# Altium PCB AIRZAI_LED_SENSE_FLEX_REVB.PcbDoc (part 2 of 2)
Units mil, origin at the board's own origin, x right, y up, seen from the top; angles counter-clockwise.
Board outline 2713.44 x 4393.69 mil, 2 copper layers (Top Layer, Bottom Layer); 53 components, 36 nets, 162 pads, 79 vias.
Unrouted connection lines stored in the file: 83.

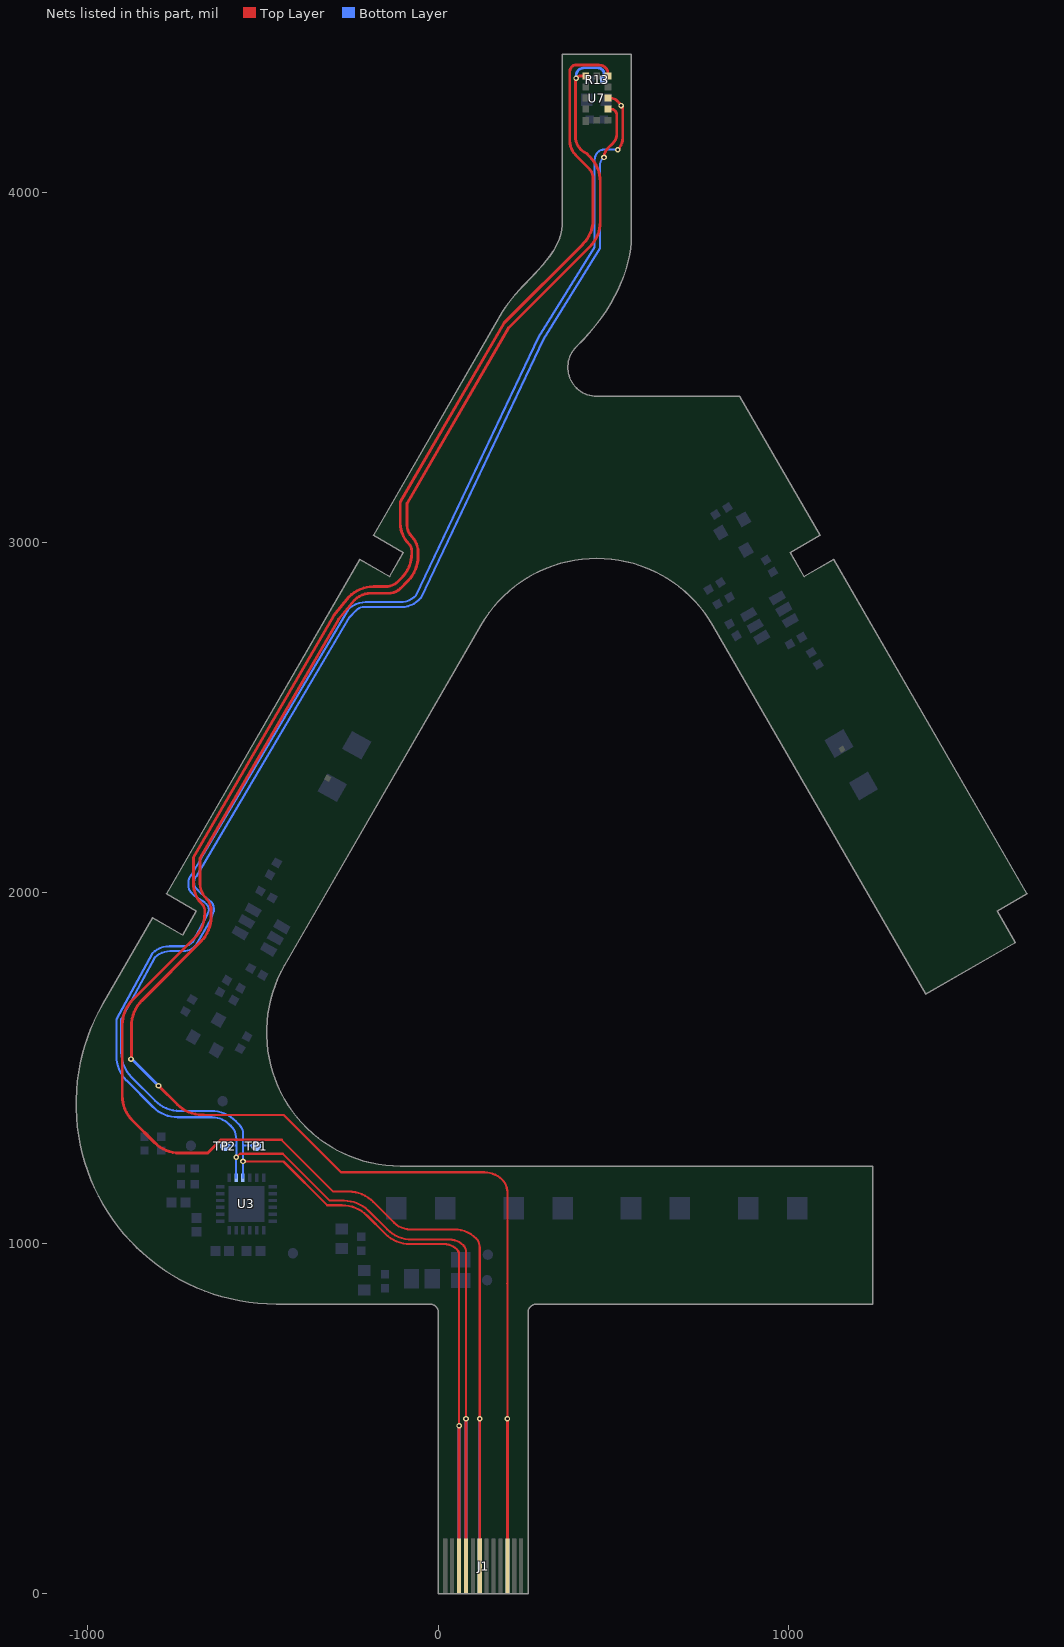
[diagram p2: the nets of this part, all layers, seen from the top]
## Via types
v1: diameter 16, hole 8, Top Layer to Bottom Layer, tented both sides, 49 vias
v2: diameter 20, hole 10, Top Layer to Bottom Layer, tented both sides, 25 vias
v3: diameter 20, hole 8, Top Layer to Bottom Layer, 5 vias

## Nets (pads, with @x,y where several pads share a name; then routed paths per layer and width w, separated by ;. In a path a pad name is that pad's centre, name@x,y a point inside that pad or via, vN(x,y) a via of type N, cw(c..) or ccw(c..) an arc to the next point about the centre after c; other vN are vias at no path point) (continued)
SCL: J1.10 TP1.1 U3.9 U7.10 | length 5932.2
  Top Layer w6: v1(-557.58,1234) -442,1234 -317,1109 -274.42,1109 cw(c-274.42,1009) -203.71,1079.71 -151.29,1027.29 ccw(c-80.58,1098) -80.58,998 16.79,998 cw(c16.79,946.79) 53,983 cw(c38.38,968.38) 59.06,968.38 v1(59.06,480)
  Top Layer w8: J1.10@59.06,78.74 v1(59.06,480) ; v1(472.68,4099) cw(c508.14,4099) 483.07,4124.07 498.39,4139.39 ccw(c472.79,4165) 509,4165 509,4218.51 ccw(c488.51,4218.51) 503,4233 ccw(c494.54,4224.54) 494.54,4236.5 U7.10@483.5,4236.5
  Bottom Layer w6: U3.9@-557.58,1187.42 v1(-557.58,1234) -557.58,1279 ; TP1.1@-520.09,1278 ccw(c-522.51,1275.59) -522.51,1279 -557.58,1279 ; v1(472.68,4099) 472.68,4101.68 ccw(c500.9,4073.47) 461,4073.47 461,3839.84 299.86,3580.26 -50,2842 -56,2836 cw(c-104.28,2884.28) -104.28,2816 -212,2816 ccw(c-212,2784.72) -234.11,2806.84 -253.65,2787.31 -690.55,2048 ccw(c-674.98,2032.43) -697,2032.43 -697,2029 ccw(c-672.08,2029) -689.7,2011.38 -676.16,1997.84 -648.57,1975 cw(c-666.86,1956.71) -641,1956.71 -641,1946.92 -649.15,1925.26 -693.49,1848.49 cw(c-728.48,1883.48) -728.48,1834 -766.1,1834 ccw(c-766.1,1773.8) -808.67,1816.37 -905,1640 -905,1545.42 ccw(c-805,1545.42) -875.71,1474.71 -808.29,1407.29 ccw(c-737.58,1478) -737.58,1378 -648.42,1378 cw(c-648.42,1278) -577.71,1348.71 -568,1339 cw(c-593.15,1313.85) -557.58,1313.85 -557.58,1279
  Bottom Layer w8: J1.10@59.06,78.74 v1(59.06,480)
SDA: J1.9 TP2.1 U3.8 U7.9 | length 6081.4
  Top Layer w6: v1(-576.57,1245.99) -566.56,1256 -444,1256 -310,1122 -269.42,1122 cw(c-269.42,1022) -198.71,1092.71 -146.29,1040.29 ccw(c-75.58,1111) -75.58,1011 32,1011 cw(c32,955.47) 71.26,994.74 72,994 cw(c55.73,977.73) 78.74,977.73 v1(78.74,499.74)
  Top Layer w8: J1.9@78.74,78.74 v1(78.74,499.74) ; U7.9@483.5,4268 490.97,4268 cw(c490.97,4238.97) 511.5,4259.5 cw(c465.63,4213.63) v1(521.48,4246.62) cw(c510.56,4235.7) 526,4235.7 526,4154.8 cw(c478.2,4154.8) v1(512,4121)
  Bottom Layer w6: TP2.1@-613.6,1278 cw(c-611.18,1275.59) -611.18,1279 -576.57,1279 ; U3.8@-577.27,1187.42 -577.27,1241.3 v1@-576.57,1241.99 ; v1(-576.57,1245.99) -576.57,1279 ; v1(512,4121) 471.9,4121 ccw(c471.9,4097.1) 455,4114 ccw(c476.73,4092.27) 446,4092.27 446,3843 286,3586 -64,2848.49 cw(c-108.63,2893.12) -108.63,2830 -207.74,2830 ccw(c-207.74,2760.9) -256.6,2809.76 -705,2051 ccw(c-685.69,2031.69) -713,2031.69 -713,2022 ccw(c-681.37,2022) -703.73,1999.63 -696.17,1992.07 -668,1974 -661.36,1967.36 cw(c-676.73,1952) -655,1952 -658.4,1940.2 -663,1931 -702,1859.59 cw(c-729.97,1887.56) -729.97,1848 -767.72,1848 ccw(c-767.72,1779.72) -816,1828 -919,1639.42 -919,1535.48 ccw(c-819,1535.48) -889.71,1464.77 -814.23,1389.29 ccw(c-743.52,1460) -743.52,1360 -646,1360 cw(c-646,1289.6) -596.22,1339.38 -591.84,1335 cw(c-628.69,1298.15) -576.57,1298.15 -576.57,1279
  Bottom Layer w8: J1.9@78.74,78.74 v1(78.74,499.74) v1@79,500
TOFINT: J1.7 U7.7 | length 6190.3
  Top Layer w6: -448,1296 -300,1148 -256.42,1148 cw(c-256.42,1048) -185.71,1118.71 -126,1059 ccw(c-80.13,1104.87) -80.13,1040 45.23,1040 cw(c45.23,951.23) 108,1014 cw(c83.59,989.59) 118.11,989.59 118.11,933.89 ; 118,934 118.11,933.89 ; v1(118.11,499.74) 118.11,933.89
  Top Layer w8: -448,1296 -620,1296 -658,1258 -738.58,1258 cw(c-738.58,1358) -809.29,1287.29 -872.71,1350.71 cw(c-802,1421.42) -902,1421.42 -902,1623.54 cw(c-802,1623.54) -872.71,1694.25 -695.73,1871.23 ccw(c-766.44,1941.94) -666.44,1941.94 -666.44,1949.2 ccw(c-693.76,1949.2) -674.44,1968.52 cw(c-615.2,2027.76) -698.98,2027.76 -698.98,2101 -298.8,2791.31 -255.63,2844.88 cw(c-184.92,2774.17) -184.92,2874.17 -150.8,2874.17 ccw(c-150.8,2924.8) -115,2889 -105.29,2898.71 ccw(c-176,2969.42) -76,2969.42 -76,2976.69 ccw(c-103.31,2976.69) -84,2996 cw(c-24.75,3055.25) -108.54,3055.25 -108.54,3115.47 188,3627 412.21,3851.21 ccw(c341.5,3921.92) 441.5,3921.92 441.5,4038 ccw(c397.86,4038) 428.72,4068.86 403.11,4094.46 391.79,4105.79 cw(c432.31,4146.31) 375,4146.31 375,4343.51 cw(c395.49,4343.51) 381,4358 cw(c391.85,4347.15) 391.85,4362.5 458.47,4362.5 cw(c458.47,4335.59) 477.5,4354.61 cw(c463.01,4340.13) 483.5,4340.13 U7.7@483.5,4330.99 ; J1.7@118.11,78.74 v1(118.11,499.74)
  Bottom Layer w8: J1.7@118.11,78.74 v1(118.11,499.74)
XSHUNT: J1.3 R13.2 U7.5 | length 6231.7
  Top Layer w6: -670.55,1367 -442,1367 -278,1203 131.3,1203 cw(c131.3,1131.3) 182,1182 cw(c146.15,1146.15) 196.85,1146.15 196.85,885.15 ; 196,886 196.85,885.15 ; v1(196.85,499.74) 196.85,885.15
  Top Layer w8: v1@-875.71,1526 -875.71,1621.87 cw(c-775.71,1621.87) -846.42,1692.58 -677.86,1861.14 ccw(c-748.57,1931.85) -648.57,1931.85 -648.57,1951.59 ccw(c-694.41,1951.59) -662,1984 cw(c-618.9,2027.1) -679.85,2027.1 -679.85,2099.9 -284.96,2781.09 -239,2836 cw(c-193.13,2790.13) -193.13,2855 -142.34,2855 ccw(c-142.34,2902.8) -108.54,2869 -87.29,2890.25 ccw(c-158,2960.96) -58,2960.96 -58,2973.54 ccw(c-119.46,2973.54) -76,3017 cw(c-44.2,3048.8) -89.17,3048.8 -89.17,3112.1 201.5,3613.5 432.4,3844.4 ccw(c361.69,3915.11) 461.69,3915.11 461.69,4029.89 ccw(c361.69,4029.89) 432.4,4100.6 422.23,4110.77 ; v1(-798.55,1450) -744.84,1396.29 ccw(c-674.13,1467) -674.13,1367 -670.55,1367 ; J1.3@196.85,78.74 v1(196.85,499.74) ; U7.5@420.5,4330.99 404.18,4330.99 ccw(c404.18,4320.88) 397.03,4328.03 393,4324 ccw(c397.83,4319.17) 391,4319.17 391,4158.91 ccw(c443.91,4158.91) 406.5,4121.5 ccw(c442.71,4157.71) 422.23,4110.77 ; 422,4111 422.23,4110.77
  Bottom Layer w8: v1(-877,1526) cw(c-877,1520.08) v1@-872.82,1524.27 ; v1@-872.81,1524.27 v1(-798.55,1450) ; J1.3@196.85,78.74 v1(196.85,499.74) ; v1(393,4325) 393,4331.1 cw(c416.9,4331.1) 400,4348 cw(c415.97,4332.03) 415.97,4354.61 454.45,4354.61 cw(c454.45,4335.45) 468,4349 cw(c456.69,4337.69) 472.69,4337.69 R13.2@472.69,4321
pads on no net: U3.11 U3.12 U3.13 U3.14 U3.15 U7.8

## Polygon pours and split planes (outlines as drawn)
GND on Bottom Layer "gnd bot" (hatched 45Degree grid 30 track 9.5, remove dead copper, pour order 8): -463,826.78 -23.39,826.77 cw(c-23.88,802.89) 0,802.41 0,0 255.91,0 255.91,802.77 cw(c279.78,802.89) 279.66,826.77 1239.37,826.77 1239.37,1220.44 -108.39,1220.47 cw(c-108.38,1602.36) -439.1,1793.32 121.28,2763.87 cw(c452,2572.92) 782.73,2763.85 1390.38,1711.31 1646.29,1858.61 1594.5,1948.32 1679.74,1997.53 1128.6,2952.19 1043.36,2902.98 1003.99,2971.17 1089.23,3020.38 860.08,3417.3 452.02,3417.31 cw(c452.02,3499.99) 394.16,3559.04 ccw(c-49.74,4012.89) 464.84,3641.1 ccw(c24.31,3959.43) 503.7,3703.33 ccw(c91.77,3922.61) 519.55,3736.13 ccw(c138.88,3902.12) 532.52,3769.79 ccw(c183.5,3887.15) 542.24,3804.11 ccw(c239.31,3875.17) 550.46,3874 550.46,3952.74 550.46,4393.69 353.61,4393.69 353.61,3952.75 353.61,3913.38 cw(c222.06,3913.41) 350.2,3883.68 cw(c204.05,3917.92) 340.75,3855.9 cw(c158.18,3938.86) 326.37,3829.65 cw(c73.79,3993.55) 308.19,3804.57 cw(c-93.59,4128.16) 287.35,3780.27 cw(c-627.68,4615.35) 264.96,3756.39 242.17,3732.54 ccw(c839.65,3165.01) 220.1,3708.36 ccw(c465.09,3488.64) 182.62,3657.47 -185.21,3020.41 -99.97,2971.2 -139.35,2903.01 -224.58,2952.23 -775.77,1997.6 -690.53,1948.38 -729.91,1880.19 -815.14,1929.41 -957.36,1683.09 ccw(c-462.98,1397.65)
3V3 on Bottom Layer "3.3V_1" (solid, remove dead copper, pour order 2): -299.03,953 ccw(c-299.08,916.43) -325,942.24 -407.37,859.87 cw(c-464.97,917.41) -465,836 -488,836.87 -531.37,840.54 -586.19,849 -625.1,859 -710,892 -772.94,928 -817,962.74 -852,993 -879,1019.83 -920,1068 -953,1122.18 -984,1183.85 -1001.44,1232.83 -1019,1301.68 -1025,1349 -1027,1414 -1023,1467 -1015,1514 -1005,1557 -992,1598 -971,1645 -945,1691 -884,1796 -829.8,1889.64 -826.08,1893.36 cw(c-803.06,1870.34) -803,1902.92 -794.09,1901.67 -781,1899 -770,1894 -734,1875 ccw(c-730.86,1879.5) -729.91,1874.09 -727.7,1874.7 ccw(c-728.35,1877.36) -726,1875.94 -722.61,1880.19 -684.76,1944 ccw(c-691.51,1947.87) -684,1950 -685,1952 ccw(c-688.28,1950.69) -687,1954 -728,1978 -740,1989 cw(c-713.9,2018.2) -753,2016 -752.07,2023.09 -751,2027 -740,2046.09 -726,2069.97 -256.34,2876 -243,2868 -727.7,2031 -732,2021 -732,2016 -729.91,2010 -727.7,2006.13 -720.59,1999.01 -709.31,1989 -698.79,1981.21 -691,1974 -685,1971 -677.3,1965.3 -669.76,1957 -666.74,1951 -666.74,1944 -673.08,1930.92 -698,1884 -707,1871 -712.2,1863.49 -722.61,1858 -742.74,1857 -785.05,1855.95 -803.8,1853.97 -815.14,1850.61 -821,1847 -829.8,1835.06 -886.05,1724.05 -922,1664 -950.5,1611.5 -974,1555 -984,1504 -992,1430 -992,1359 -982,1281 -960.43,1207.43 -929.11,1137.89 -901.5,1083.5 -869,1041.25 -829.8,1005 -764.28,950 -704,912.78 -623,884 -576.26,872.48 -524,865 -475,866 -444.15,876 -422,892.73 -406,913 -389,935 -370,958 -354,975 -336,993 -325,997.62 -285,998 -284,998 -284,953
3V3 on Bottom Layer "3.3V_1" (solid, remove dead copper, pour order 4): -260.83,2868 -250.66,2886.36 -245.88,2891.14 cw(c-210,2855.26) -210,2906 -198.8,2906 cw(c-198.8,2858.21) -165,2892 ccw(c-150.51,2906.49) -150.51,2886 -142.34,2886 ccw(c-142.34,2913.58) -122.84,2894.08 -119.92,2897 -81,2963 -50,3020.41 220,3596 350,3818 ccw(c319.84,3848.17) 362.5,3848.17 362.5,4048 427.5,4048 427.5,3968 428,3846 371,3747 272,3594 177,3391 -66.91,2882.09 cw(c-107.5,2886.58) -112,2846 -137,2846 -172,2855 -204,2868 ccw(c-220.9,2851.11) -220.9,2875 -228,2875 ccw(c-228,2862.18) -237.07,2871.24 -247.32,2861 -249.67,2863.35 ccw(c-260.88,2852.15) -260.88,2868 -250.02,2887
NetJ1_12 on Bottom Layer "Bottom Layer-NetJ1_12" (solid, remove dead copper, pour order 0): 40,806 40,817.86 ccw(c5.86,817.86) 30,842 24.9,847.1 cw(c48.8,871) 15,871 15,926.5 -39,926.5 -39.3,926.19 -39.3,858.15 ccw(c-24.61,858.15) -35,847.76 -27.78,840.54 ccw(c-19.24,849.07) -19.24,837 -13,837 cw(c-13,810.44) 5.78,829.22 6,829 cw(c-3.66,819.34) 10,819.34 10,806
no net on Mechanical 4 (solid, pour order 5): -284,953
GND on Top Layer "gnd top" (hatched 45Degree grid 30 track 9.5, remove dead copper, pour order 7): -463,826.78 -23.39,826.77 cw(c-23.88,802.89) 0,802.41 0,0 255.91,0 255.91,802.77 cw(c279.78,802.89) 279.66,826.77 1239.37,826.77 1239.37,1220.44 -108.39,1220.47 cw(c-108.38,1602.36) -439.1,1793.32 121.28,2763.87 cw(c452,2572.92) 782.73,2763.85 1390.38,1711.31 1646.29,1858.61 1594.5,1948.32 1679.74,1997.53 1128.6,2952.19 1043.36,2902.98 1003.99,2971.17 1089.23,3020.38 860.08,3417.3 452.02,3417.31 cw(c452.02,3499.99) 394.16,3559.04 ccw(c-49.74,4012.89) 464.84,3641.1 ccw(c24.31,3959.43) 503.7,3703.33 ccw(c91.77,3922.61) 519.55,3736.13 ccw(c138.88,3902.12) 532.52,3769.79 ccw(c183.5,3887.15) 542.24,3804.11 ccw(c239.31,3875.17) 550.46,3874 550.46,3952.74 550.46,4393.69 353.61,4393.69 353.61,3952.75 353.61,3913.38 cw(c222.06,3913.41) 350.2,3883.68 cw(c204.05,3917.92) 340.75,3855.9 cw(c158.18,3938.86) 326.37,3829.65 cw(c73.79,3993.55) 308.19,3804.57 cw(c-93.59,4128.16) 287.35,3780.27 cw(c-627.68,4615.35) 264.96,3756.39 242.17,3732.54 ccw(c839.65,3165.01) 220.1,3708.36 ccw(c465.09,3488.64) 182.62,3657.47 -185.21,3020.41 -99.97,2971.2 -139.35,2903.01 -224.58,2952.23 -775.77,1997.6 -690.53,1948.38 -729.91,1880.19 -815.14,1929.41 -957.36,1683.09 ccw(c-462.98,1397.65)

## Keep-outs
Keep-Out Layer:
  lines w1.97: -327.65,2347.93 -286.55,2419.3 -208.08,2374.12 -249.18,2302.74 -327.65,2347.93 ; -91.34,1055.11 -8.67,1055.11 -8.67,1145.67 -91.34,1145.67 -91.34,1055.11 ; 243.29,1055.11 325.97,1055.11 325.97,1145.66 243.29,1145.66 243.29,1055.11 ; 577.94,1055.12 660.62,1055.12 660.62,1145.67 577.94,1145.67 577.94,1055.12 ; 912.59,1055.09 995.27,1055.09 995.27,1145.64 912.59,1145.64 912.59,1055.09 ; 1118.5,2378.93 1196.97,2424.11 1238.07,2352.74 1159.59,2307.55 1118.5,2378.93
  lines w5: -957.36,1683.09 ccw(c-462.98,1397.65) -463,826.78 -23.39,826.77 cw(c-23.88,802.89) 0,802.41 0,0 255.91,0 255.91,802.77 cw(c279.78,802.89) 279.66,826.77 1239.37,826.77 1239.37,1220.44 -108.39,1220.47 cw(c-108.38,1602.36) -439.1,1793.32 121.28,2763.87 cw(c452,2572.92) 782.73,2763.85 1390.38,1711.31 1646.29,1858.61 1594.5,1948.32 1679.74,1997.53 1128.6,2952.19 1043.36,2902.98 1003.99,2971.17 1089.23,3020.38 860.08,3417.3 452.02,3417.31 cw(c452.02,3499.99) 394.16,3559.04 ccw(c-49.74,4012.89) 464.84,3641.1 ccw(c24.31,3959.43) 503.7,3703.33 ccw(c91.77,3922.61) 519.55,3736.13 ccw(c138.88,3902.12) 532.52,3769.79 ccw(c183.5,3887.15) 542.24,3804.11 ccw(c239.31,3875.17) 550.46,3874 550.46,3952.74 550.46,4393.69 353.61,4393.69 353.61,3952.75 353.61,3913.38 cw(c222.06,3913.41) 350.2,3883.68 cw(c204.05,3917.92) 340.75,3855.9 cw(c158.18,3938.86) 326.37,3829.65 cw(c73.79,3993.55) 308.19,3804.57 cw(c-93.59,4128.16) 287.35,3780.27 cw(c-627.68,4615.35) 264.96,3756.39 242.17,3732.54 ccw(c839.65,3165.01) 220.1,3708.36 ccw(c465.09,3488.64) 182.62,3657.47 -185.21,3020.41 -99.97,2971.2 -139.35,2903.01 -224.58,2952.23 -775.77,1997.6 -690.53,1948.38 -729.91,1880.19 -815.14,1929.41 -957.36,1683.09

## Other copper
Top Layer:
  rectangle net +5V: -528,878.24 -252,939
  pour cut-out: 1196.82,2424.27 1238.16,2352.67 1159.59,2307.55 1118.4,2378.99 1196.97,2424.11
  pour cut-out: -286.55,2419.3 -208.08,2374.12 -249.18,2302.74 -327.61,2348 -286.73,2419
  pour cut-out: 912.59,1145.62 995.27,1145.62 995.27,1055.07 912.59,1055.07
  pour cut-out: 577.95,1145.63 660.62,1145.63 660.62,1055.08 577.95,1055.08
  pour cut-out: 243.31,1145.66 325.99,1145.66 325.99,1055.11 243.31,1055.11
  pour cut-out: -91.36,1145.67 -8.68,1145.67 -8.68,1055.12 -91.36,1055.12
  pour cut-out: 0,177.4 0,0 257.9,0 257.9,177.4
Bottom Layer:
  rectangle net GND: -401,1117.23 -372,1171
  rectangle net 3V3: 419,4274 445,4336.75
  rectangle net +5V: -304,881 -251,938
  rectangle net +5V: -527.69,879 -462,939
  rectangle net 3V3: -325,952.8 92,997.62
  rectangle net +5V: -276,902.17 -55,937.78
  rectangle net NetJ1_11: 47,532 77,894.47
  rectangle net NetJ1_12: 10,532 40,816
  rectangle net 3V3: 378.77,4139.33 432.5,4308.5
  rectangle net 3V3: 362.5,4030 427.5,4308.5
  pour cut-out: -286.64,2419.15 -208.08,2374.12 -249.18,2302.74 -327.65,2347.93 -286.55,2419.3
  pour cut-out: 1196.89,2424.19 1238.16,2352.67 1159.59,2307.55 1118.4,2378.99 1196.82,2424.27
  pour cut-out: 577.95,1145.65 577.95,1055.1 660.63,1055.1 660.64,1055.12 660.64,1145.65 577.96,1145.65
  pour cut-out: 912.67,1145.25 912.67,1054.7 995.35,1054.7 995.36,1054.72 995.36,1145.25 912.68,1145.25
  pour cut-out: 243.31,1145.66 243.31,1055.11 325.99,1055.11 326,1055.12 326,1145.66 243.31,1145.66
  pour cut-out: -91.36,1145.67 -91.36,1055.12 -8.68,1055.12 -8.67,1055.13 -8.67,1145.67 -91.35,1145.67
  pour cut-out: -634.35,1198.83 cw(c-635.61,1197.57) -633.83,1197.57 -633.83,1025.39 -463.15,1025.39 -463.15,1199.23 -633.69,1199.23
  pour cut-out: 959.91,2495.26 1180.9,2105.25 1181.9,2103.25 1218.9,2120.25 1403.9,2228.25 1387.9,2265.01 1182.9,2616.25 1181.9,2619.25
  pour cut-out: -71.99,2501.64 -292.98,2111.63 -293.98,2109.63 -330.98,2126.63 -515.98,2234.63 -499.98,2271.39 -294.98,2622.63 -293.98,2625.63
  pour cut-out: 0,177.4 0,0 256.9,0 256.9,177.4

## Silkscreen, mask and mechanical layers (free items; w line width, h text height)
Mechanical 1:
  drawing of 2386 lines, arcs and shapes, not listed
  text "5" at 8156.7,4325.32 h137.8
  text "10,4" at -3104,4297 h137.8
  text "R2,1" at 506.89,3695.85 h137.8 r16.49
  text "R9,7" at 437.26,2998.71 h137.8 r295.83
  text "44,27" at 1708.78,2900.9 h137.8 r300
  text "44,27" at 6753.43,2783.45 h137.8 r60
  text "10" at 539.61,2504.29 h137.8 r30
  text "10" at -772.78,2485.04 h137.8 r330
  text "79,4" at 5488.08,2228.2 h137.8 r90
  text "65,8" at 5849.36,2115.99 h137.8 r90
  text "R9,7" at -1251.32,1934.38 h137.8 r352.12
  text "0,4" at -2643.99,1476.02 h137.8
  text "10" at 2083.24,1406.29 h137.8 r90
  text "R14,5" at -1410.39,1246.65 h137.8 r19.4
  text "57,74" at 7999.21,512.6 h137.8
Mechanical 2:
  region: 214.6,824.04 214.6,1033.94 68.28,1033.94 68.28,824.04
  region: -327.03,858 -327.03,1090.6 -481.16,1090.6 -481.16,858
  region: -484,1238.05 -484,1441.52 -774.43,1441.52 -774.43,1238.05
  rectangle: 0,0 255.91,178
  lines w5: -734.14,524 -543,524 -293,524 51.88,868.88 ; -558.78,1213.22 -542,1230 ; -542,524 -542,1230 ; -524,1211 -542,1229 -542,1230 ; -414,835.22 -401.17,848.05 ; -387,834.98 -400.07,848.05 -401.17,848.05 ; -28,75 -7,88 ; -28,101 -7,88 ; 28.88,868.88 51.88,868.88 ; 51.88,848.88 51.88,868.88 ; -401.17,848.05 -401.17,667.83 -543,526 -105,88 -7,88
  text "Stiffener Location" at -1272,507 h30
Mechanical 3:
  lines w6: 518.57,4228.19 518.57,4247.19
Mechanical 4:
  lines w1.97: -327.65,2347.93 -286.55,2419.3 -208.08,2374.12 -249.18,2302.74 -327.65,2347.93 ; -91.34,1055.11 -8.67,1055.11 -8.67,1145.67 -91.34,1145.67 -91.34,1055.11 ; 243.29,1055.11 325.97,1055.11 325.97,1145.66 243.29,1145.66 243.29,1055.11 ; 577.94,1055.12 660.62,1055.12 660.62,1145.67 577.94,1145.67 577.94,1055.12 ; 912.59,1055.09 995.27,1055.09 995.27,1145.64 912.59,1145.64 912.59,1055.09 ; 1118.5,2378.93 1159.59,2307.55 1238.07,2352.74 1196.97,2424.11 1118.5,2378.93
  lines w5: -957.36,1683.09 ccw(c-462.98,1397.65) -463,826.78 -23.39,826.77 cw(c-23.88,802.89) 0,802.41 0,0 255.91,0 255.91,802.77 cw(c279.78,802.89) 279.66,826.77 1239.37,826.77 1239.37,1220.44 -108.39,1220.47 cw(c-108.38,1602.36) -439.1,1793.32 121.28,2763.87 cw(c452,2572.92) 782.73,2763.85 1390.38,1711.31 1646.29,1858.61 1594.5,1948.32 1679.74,1997.53 1128.6,2952.19 1043.36,2902.98 1003.99,2971.17 1089.23,3020.38 860.08,3417.3 452.02,3417.31 cw(c452.02,3499.99) 394.16,3559.04 ccw(c-49.74,4012.89) 464.84,3641.1 ccw(c24.31,3959.43) 503.7,3703.33 ccw(c91.77,3922.61) 519.55,3736.13 ccw(c138.88,3902.12) 532.52,3769.79 ccw(c183.5,3887.15) 542.24,3804.11 ccw(c239.31,3875.17) 550.46,3874 550.46,3952.74 550.46,4393.69 353.61,4393.69 353.61,3952.75 353.61,3913.38 cw(c222.06,3913.41) 350.2,3883.68 cw(c204.05,3917.92) 340.75,3855.9 cw(c158.18,3938.86) 326.37,3829.65 cw(c73.79,3993.55) 308.19,3804.57 cw(c-93.59,4128.16) 287.35,3780.27 cw(c-627.68,4615.35) 264.96,3756.39 242.17,3732.54 ccw(c839.65,3165.01) 220.1,3708.36 ccw(c465.09,3488.64) 182.62,3657.47 -185.21,3020.41 -99.97,2971.2 -139.35,2903.01 -224.58,2952.23 -775.77,1997.6 -690.53,1948.38 -729.91,1880.19 -815.14,1929.41 -957.36,1683.09
Mechanical 12:
  circle w0.5: c-266.51,2360.24 r98.43
  circle w0.5: c1190.18,2360.21 r98.43
  circle w0.5: c-266.51,2360.24 r59.06
  circle w0.5: c1190.18,2360.21 r59.06
  circle w0.5: c953.93,1100.37 r98.43
  circle w0.5: c619.28,1100.38 r98.43
  circle w0.5: c284.64,1100.39 r98.43
  circle w0.5: c-50.01,1100.39 r98.43
  circle w0.5: c953.93,1100.37 r59.06
  circle w0.5: c619.28,1100.38 r59.06
  circle w0.5: c284.64,1100.39 r59.06
  circle w0.5: c-50.01,1100.39 r59.06
  circle w0.5: c953.92,1100.37 r98.43
  circle w0.5: c619.27,1100.38 r98.43
  circle w0.5: c284.63,1100.39 r98.43
  circle w0.5: c-50.02,1100.4 r98.43
  circle w0.5: c953.92,1100.37 r59.06
  circle w0.5: c619.27,1100.38 r59.06
  circle w0.5: c284.63,1100.39 r59.06
  circle w0.5: c-50.02,1100.4 r59.06
  lines w0.5: 3216.56,-822.41 3216.56,-842.1 3413.41,-842.1 3413.41,-822.41 ; 3316.56,4765.63 3316.56,4785.31 3513.41,4785.31 3513.41,4765.63 ; 3452.81,-822.41 3452.81,-842.1 3649.66,-842.1 3649.66,-822.41 ; 3552.81,4765.63 3552.81,4785.31 3749.66,4785.31 3749.66,4765.63 ; 3787.46,-822.41 3787.46,-842.1 3984.31,-842.1 3984.31,-822.41 ; 3887.46,4765.63 3887.46,4785.31 4084.31,4785.31 4084.31,4765.63 ; 3905.61,995.94 3925.29,995.94 ; 3905.61,995.98 3905.61,1192.76 3925.29,1192.79 ; 3905.61,2255.78 3925.29,2255.78 ; 3905.61,2255.81 3905.61,2452.6 ; 3905.61,2452.63 3925.29,2452.63 ; 4122.1,-822.41 4122.1,-842.1 4318.95,-842.1 4318.95,-822.41 ; 4222.1,4765.63 4222.1,4785.31 4418.95,4785.31 4418.95,4765.63 ; 4456.75,-822.41 4456.75,-842.1 4653.6,-842.1 4653.6,-822.41 ; 4556.75,4765.63 4556.75,4785.31 4753.6,4785.31 4753.6,4765.63 ; 4673.25,-822.41 4673.25,-842.1 4870.1,-842.1 4870.1,-822.41 ; 4773.25,4765.63 4773.25,4785.31 4970.1,4785.31 4970.1,4765.63 ; 6284.03,2804.23 cw(c6295.04,2746.21) 6295.04,2805.26 ; 6323.32,2694.36 ccw(c6295.04,2746.21) 6329.47,2698.23 ; 6351.17,2764.56 cw(c6295.04,2746.21) 6353.87,2741.01 ; 6489.53,1528.13 cw(c6531.29,1486.37) 6494.23,1532.35 ; 6489.53,1444.61 ccw(c6531.29,1486.37) 6494.23,1440.39 ; 6568.35,1440.39 ccw(c6531.29,1486.37) 6573.05,1444.61 ; 6568.35,1532.35 cw(c6531.29,1486.37) 6573.05,1528.13 ; 6824.18,1444.62 ccw(c6865.94,1486.38) 6828.88,1440.4 ; 6824.18,1528.14 cw(c6865.94,1486.38) 6828.88,1532.36 ; 6903,1440.4 ccw(c6865.94,1486.38) 6907.7,1444.62 ; 6903,1532.36 cw(c6865.94,1486.38) 6907.7,1528.14 ; 7067.97,2412.23 cw(c7078.98,2354.21) 7078.98,2413.26 ; 7107.26,2302.36 ccw(c7078.98,2354.21) 7113.42,2306.23 ; 7135.11,2372.56 cw(c7078.98,2354.21) 7137.81,2349.01 ; 7158.83,1444.63 ccw(c7200.58,1486.39) 7163.52,1440.41 ; 7158.82,1528.14 cw(c7200.58,1486.39) 7163.52,1532.36 ; 7237.65,1440.41 ccw(c7200.58,1486.39) 7242.34,1444.63 ; 7237.64,1532.37 cw(c7200.58,1486.39) 7242.34,1528.15 ; 7273.48,1052.61 ccw(c7315.24,1094.37) 7278.18,1048.39 ; 7273.48,1136.13 cw(c7315.24,1094.37) 7278.17,1140.35 ; 7352.3,1048.39 ccw(c7315.24,1094.37) 7357,1052.61 ; 7352.3,1140.35 cw(c7315.24,1094.37) 7356.99,1136.13 ; 7493.47,1444.64 ccw(c7535.23,1486.4) 7498.17,1440.42 ; 7493.47,1528.15 cw(c7535.23,1486.4) 7498.17,1532.37 ; 7572.29,1440.42 ccw(c7535.23,1486.4) 7576.99,1444.64 ; 7572.29,1532.37 cw(c7535.23,1486.4) 7576.99,1528.15 ; 7608.12,1052.62 ccw(c7649.88,1094.38) 7612.82,1048.4 ; 7608.12,1136.13 cw(c7649.88,1094.38) 7612.82,1140.35 ; 7686.94,1048.4 ccw(c7649.88,1094.38) 7691.64,1052.62 ; 7686.94,1140.36 cw(c7649.88,1094.38) 7691.64,1136.14 ; 7803.52,2774.63 cw(c7751.73,2746.24) 7806.77,2767.65 ; 7942.77,1052.63 ccw(c7984.53,1094.39) 7947.47,1048.41 ; 7942.77,1136.14 cw(c7984.53,1094.39) 7947.47,1140.36 ; 8021.59,1048.41 ccw(c7984.53,1094.39) 8026.29,1052.63 ; 8021.59,1140.37 cw(c7984.53,1094.39) 8026.28,1136.15 ; 8277.42,1052.63 ccw(c8319.17,1094.39) 8282.11,1048.41 ; 8277.41,1136.15 cw(c8319.17,1094.39) 8282.11,1140.37 ; 8356.23,1140.37 cw(c8319.17,1094.39) 8360.93,1136.15 ; 8356.23,1048.42 ccw(c8319.17,1094.39) 8360.93,1052.64 ; 8587.46,2382.63 cw(c8535.68,2354.24) 8590.71,2375.65
Drill Drawing:
  text "PWB, LED SENSE FLEX" at 7553.47,-3644.84 h157.48
  text "PWB-020218-001" at 7740.48,-3970.63 h127.95
  text "1" at 10165.68,-4029.68 h78.74
  text "1" at 9976.7,-4033.62 h78.74
Mechanical 17:
  text "PWA, LED SENSE FLEX" at 7596.1,-3719.43 h157.48
  text "PWA-020218-001" at 7790.1,-4010.43 h127.95
  text "1" at 9968.83,-4021.81 h59.06
  text "1" at 10157.8,-4021.81 h59.06
  text "NOTES: /  / 1. ALL ASSEMBLY MATERIALS TO BE RoHS COMPLIANT. /  / 2. MATERIAL: /           • FLEXIBLE METAL CLAD DIELECTRIC IAW                 /             IPC-4204/11 E1E2 O0/0 CU W7 T/T /           • STIFFENER IAW IPC-4203/1-E1E8M1 /  / 3. FINISH:  IMMERSION GOLD /  / ALL EXPOSED CONDUCTIVE PATTERN AREAS NOT COVERED WITH COVERLAY MATERIAL OR OTHER PLATING  / SHALL BE IMMERSION GOLD (0.000030-0.000090 mm) OVER ELECTROLESS NICKEL (0.001-0.006 mm). /  / 4. LEGEND SHALL BE WHITE, PERMANENT, ORGANIC, NON-CONDUCTIVE UV OR EPOXY TYPE INK APPLIED  / TO THE TOP SIDE OF THE BOARD. THERE SHALL BE NO LEGEND ON ANY SOLDERABLE COMPONENT LAND. /  / 5. ALL ASSEMBLY MATERIALS TO BE RoHS COMPLIANT. /  / 6. ANY LABELS OR COMPOSITION OF, APPLIED TO THE BOARD NEED TO BE APPROVIED BY AIRZAI /  / 7. MINIMUM TRACE WIDTHS: /           EXTERNAL: 0.203 mm  INTERNAL: N/A /  / 8. MINIMUM SPACE BETWEEN FEATURES: /          EXTERNAL: 0.15 mm  INTERNAL: N/A /  / 9. Overall Board Thickness: 0.1mm" at -3819,-4171 h78.74
Mechanical 18:
  lines w5: -4122.85,-1925.75 -3922.85,-1925.75 ; -4122.85,449.25 -3922.85,449.25 ; -4122.85,2824.25 -3922.85,2824.25 ; -1622.85,-4300.75 -1622.85,-4100.75 ; -1622.85,4999.25 -1622.85,5199.25 ; 877.15,-4300.75 877.15,-4100.75 ; 877.15,4999.25 877.15,5199.25 ; 3377.15,-4300.75 3377.15,-4100.75 ; 3377.15,4999.25 3377.15,5199.25 ; 5877.15,-4300.75 5877.15,-4100.75 ; 5877.15,4999.25 5877.15,5199.25 ; 6176.35,-3802.97 10676.35,-3802.97 ; 6176.35,-3561.23 7247.02,-3561.23 ; 6176.35,-3327.18 7247.02,-3327.18 ; 6176.35,-3116.35 7247.02,-3116.35 ; 6177.15,-4100.75 10677.15,-4100.75 ; 6802.14,-4103.95 6802.14,-2903.95 ; 7247.02,-4102.97 7247.02,-2902.97 ; 7247.02,-3436.04 10676.2,-3436.04 ; 7586.98,-2902.97 10676.35,-2902.97 ; 7676.35,-2902.97 6176.35,-2902.97 ; 8377.15,-4300.75 8377.15,-4100.75 ; 8377.15,4999.25 8377.15,5199.25 ; 10299.97,-4102.97 10299.97,-3802.97 ; 10677.15,-2900.75 10677.15,-4100.75 ; 10677.15,-1925.75 10877.15,-1925.75 ; 10677.15,449.25 10877.15,449.25 ; 10677.15,2824.25 10877.15,2824.25 ; 4776.35,-4102.97 6176.35,-4102.97 ; 4776.35,-4102.97 6176.35,-4102.97 ; 4776.35,-4102.97 4776.35,-2902.97 6176.35,-2902.97 ; 6176.35,-4102.97 10676.35,-4102.97 ; 6176.35,-4102.97 10676.35,-4102.97 ; 6176.35,-4102.97 6176.35,-2902.97 ; 10676.35,-4102.97 10676.35,-2902.97 ; 10676.35,-4102.97 10676.35,-2902.97 ; 10677.15,-4100.75 10677.15,4999.25 -3922.85,4999.25 -3922.85,-4100.75 10677.15,-4100.75 ; -4122.85,-4300.75 -4122.85,5199.25 10877.15,5199.25 10877.15,-4300.75 -4122.85,-4300.75
  text "1" at -2891.51,5069.25 h70
  text "2" at -395.85,5069.25 h70
  text "3" at 2093.49,5069.25 h70
  text "4" at 4600.16,5069.25 h70
  text "5" at 7099.15,5069.25 h70
  text "6" at 9604.15,5069.25 h70
  text "A" at -4047.85,3926.25 h70
  text "A" at 10752.15,3926.25 h70
  text "B" at -4047.85,1546.25 h70
  text "B" at 10752.15,1546.25 h70
  text "C" at -4047.85,-828.75 h70
  text "C" at 10752.15,-828.75 h70
  text "AIRZAI PROPRIETARY & CONFIDENTIAL" at 6332.27,-2792.09 h127.95
  text "DATE:" at 6832.65,-2965.17 h45
  text "ENGINEER:" at 6198.79,-2971.47 h45
  text "UNLESS OTHERWISE SPECIFIED" at 4875.96,-3032.1 h59.06
  text "05/13/19" at 6839.98,-3073.78 h59.06
  text "FD" at 6391.67,-3080.05 h78.74
  text "DIMENSIONS ARE IN MM" at 4998.01,-3158.08 h59.06
  text "PCB DESIGNER:" at 6194.86,-3179.86 h45
  text "DATE:" at 6820.84,-3181.71 h45
  text "D" at -4047.85,-3198.75 h70
  text "D" at 10752.15,-3198.75 h70
  text "AIRZAI" at 7537.98,-3236.97 h127.95
  text "TOLERANCES" at 5198.79,-3284.07 h59.06
  text "05/13/19" at 6839.98,-3288.35 h59.06
  text "DFM" at 6365.29,-3289.93 h78.74
  text "DATE:" at 6820.84,-3394.3 h45
  text "CHECK" at 6194.86,-3396.39 h45
  text "ANGULAR" at 5683.05,-3441.55 h59.06
  text "DECIMALS" at 4879.9,-3453.36 h59.06
  text "TITLE:" at 7298.8,-3499.77 h45
  text "FD" at 6431.04,-3513.12 h78.74
  text ".XX +/- .127MM" at 4832.65,-3610.84 h59.06
  text "+/-" at 5671.23,-3614.78 h59.06
  text "REL" at 6206.67,-3627.38 h45
  text "DATE:" at 6836.59,-3634.46 h45
  text "FD" at 6421.2,-3729.66 h78.74
  text ".XXX +/- .080MM" at 4820.84,-3772.26 h59.06
  text "REV:" at 10322.42,-3866.75 h45
  text "SCALE:" at 6842.1,-3867.53 h45
  text "DWG NO:" at 7293.28,-3875.41 h45
  text "SIZE" at 6206.67,-3878.56 h45
  text "B" at 6410.41,-4009.15 h120
  text "DO NOT SCALE DRAWING" at 4875.96,-4012.41 h70.87
  text "B" at 10406.09,-4028.31 h120
  text "1:1" at 6890.72,-4032.77 h120
  text "SHEET" at 9757.85,-4064.38 h45
  text "OF" at 10021.63,-4064.38 h45
  text "1" at -2891.51,-4230.75 h70
  text "2" at -395.85,-4230.75 h70
  text "3" at 2093.49,-4230.75 h70
  text "4" at 4600.16,-4230.75 h70
  text "5" at 7099.15,-4230.75 h70
  text "6" at 9604.15,-4230.75 h70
